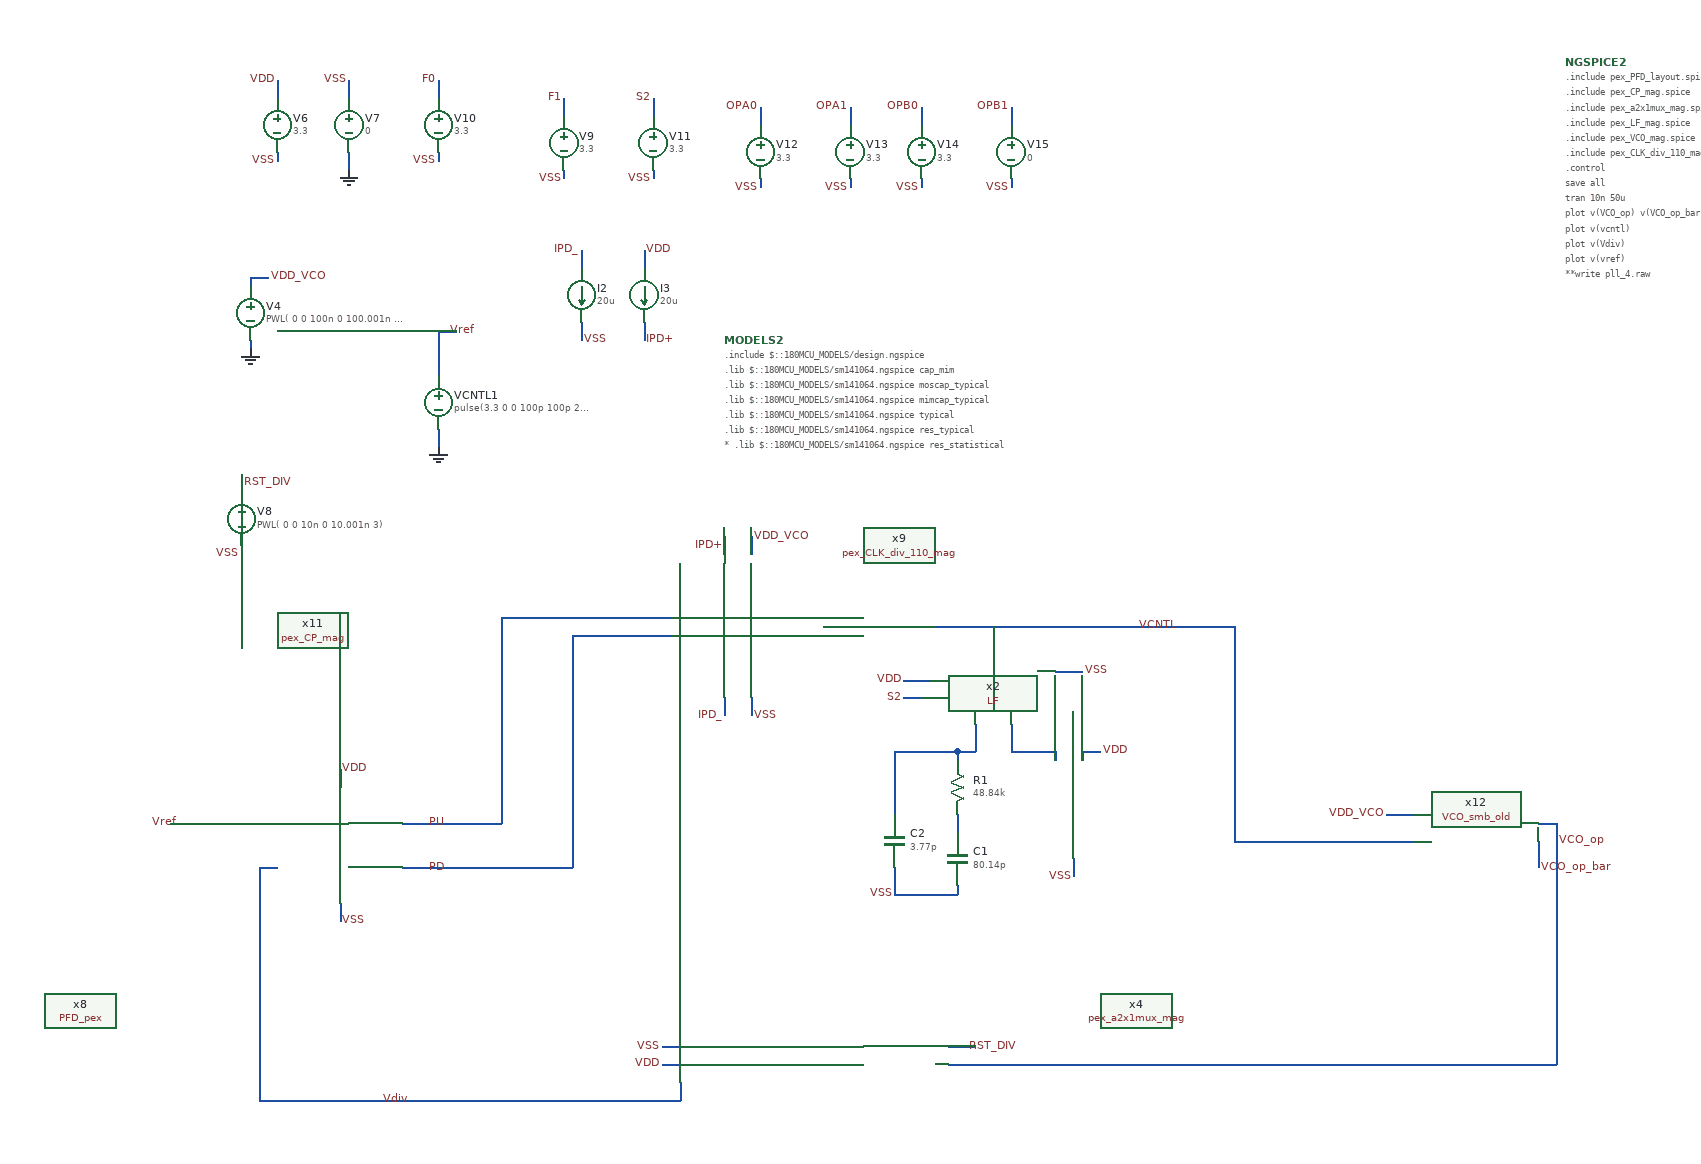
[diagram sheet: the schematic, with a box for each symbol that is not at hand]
v {xschem version=3.1.0 file_version=1.2
}
G {}
K {}
V {}
S {}
E {}
N 2610 -1220 2610 -1200 {
lab=VDD}
N 2610 -1070 2610 -1050 {
lab=VSS}
N 2520 -1160 2540 -1160 {
lab=Vref}
N 2520 -1110 2540 -1110 {
lab=Vdiv}
N 2680 -1110 2700 -1110 {
lab=PD}
N 2440 -1160 2500 -1160 {
lab=Vref}
N 2500 -1160 2520 -1160 {
lab=Vref}
N 2700 -1160 2790 -1160 {
lab=PU}
N 2700 -1110 2790 -1110 {
lab=PD}
N 2520 -1110 2520 -980 {
lab=Vdiv}
N 2520 -880 2520 -850 {
lab=Vdiv}
N 2530 -850 2820 -850 {
lab=Vdiv}
N 2520 -980 2520 -880 {
lab=Vdiv}
N 2520 -850 2530 -850 {
lab=Vdiv}
N 2680 -1160 2700 -1160 {
lab=PU}
N 2720 -1600 2720 -1580 {
lab=GND}
N 2510 -1700 2510 -1690 {
lab=GND}
N 2720 -1710 2740 -1710 {
lab=Vref}
N 2540 -1910 2540 -1900 {
lab=VSS}
N 2540 -1990 2540 -1970 {
lab=VDD}
N 2620 -1990 2620 -1970 {
lab=VSS}
N 2620 -1910 2620 -1890 {
lab=GND}
N 2820 -850 2990 -850 {
lab=Vdiv}
N 3320 -890 3970 -890 {
lab=VCO_op}
N 2500 -1470 2500 -1460 {
lab=VSS}
N 2500 -1550 2500 -1530 {
lab=RST_DIV}
N 3970 -1140 3970 -1120 {
lab=VCO_op}
N 2720 -1710 2720 -1660 {
lab=Vref}
N 3290 -890 3310 -890 {
lab=VCO_op}
N 3310 -890 3320 -890 {
lab=VCO_op}
N 3970 -1120 3970 -890 {
lab=VCO_op}
N 2510 -1770 2510 -1760 {
lab=VDD_VCO}
N 2510 -1770 2530 -1770 {
lab=VDD_VCO}
N 2860 -1890 2860 -1880 {
lab=VSS}
N 2860 -1970 2860 -1950 {
lab=F1}
N 2720 -1910 2720 -1900 {
lab=VSS}
N 2720 -1990 2720 -1970 {
lab=F0}
N 2960 -1890 2960 -1880 {
lab=VSS}
N 2960 -1970 2960 -1950 {
lab=S2}
N 3080 -1880 3080 -1870 {
lab=VSS}
N 3080 -1960 3080 -1940 {
lab=OPA0}
N 3180 -1880 3180 -1870 {
lab=VSS}
N 3180 -1960 3180 -1940 {
lab=OPA1}
N 3260 -1880 3260 -1870 {
lab=VSS}
N 3260 -1960 3260 -1940 {
lab=OPB0}
N 3360 -1880 3360 -1870 {
lab=VSS}
N 3360 -1960 3360 -1940 {
lab=OPB1}
N 3070 -1480 3070 -1460 {
lab=VDD_VCO}
N 3070 -1300 3070 -1280 {
lab=VSS}
N 2960 -1390 2980 -1390 {
lab=PU}
N 2960 -1370 2980 -1370 {
lab=PD}
N 3040 -1480 3040 -1460 {
lab=IPD+}
N 3040 -1300 3040 -1280 {
lab=IPD_}
N 2880 -1720 2880 -1700 {
lab=VSS}
N 2950 -1720 2950 -1700 {
lab=IPD+}
N 2880 -1800 2880 -1780 {
lab=IPD_}
N 2950 -1800 2950 -1780 {
lab=VDD}
N 2420 -1160 2450 -1160 {
lab=Vref}
N 3610 -1140 3650 -1140 {
lab=VCNTL}
N 3970 -1160 3970 -1140 {
lab=VCO_op}
N 3950 -1160 3970 -1160 {
lab=VCO_op}
N 3950 -1140 3950 -1110 {
lab=VCO_op_bar}
N 2990 -870 2990 -850 {
lab=Vdiv}
N 2980 -890 2990 -890 {
lab=VDD}
N 2970 -890 2980 -890 {
lab=VDD}
N 2970 -910 2990 -910 {
lab=VSS}
N 3290 -910 3320 -910 {
lab=RST_DIV}
N 3780 -1170 3810 -1170 {
lab=VDD_VCO}
N 3650 -1140 3810 -1140 {
lab=VCNTL}
N 3430 -1120 3430 -1100 {
lab=VSS}
N 3440 -1240 3440 -1230 {
lab=VDD}
N 3440 -1240 3460 -1240 {
lab=VDD}
N 3240 -1300 3260 -1300 {
lab=S2}
N 3240 -1320 3260 -1320 {
lab=VDD}
N 3410 -1330 3440 -1330 {
lab=VSS}
N 3230 -1110 3230 -1080 {
lab=VSS}
N 3230 -1080 3300 -1080 {
lab=VSS}
N 3230 -1240 3230 -1170 {
lab=#net1}
N 3230 -1240 3300 -1240 {
lab=#net1}
N 3300 -1240 3300 -1230 {
lab=#net1}
N 3260 -1320 3270 -1320 {
lab=VDD}
N 3220 -1380 3400 -1380 {
lab=VCNTL}
N 3300 -1170 3300 -1150 {
lab=#net2}
N 3300 -1090 3300 -1080 {
lab=VSS}
N 3300 -1240 3320 -1240 {
lab=#net1}
N 3320 -1270 3320 -1240 {
lab=#net1}
N 3410 -1240 3410 -1230 {
lab=#net3}
N 3360 -1240 3410 -1240 {
lab=#net3}
N 3360 -1270 3360 -1240 {
lab=#net3}
N 3340 -1380 3340 -1370 {
lab=VCNTL}
N 3610 -1370 3610 -1140 {
lab=VCNTL}
N 3610 -1380 3610 -1370 {
lab=VCNTL}
N 3400 -1380 3610 -1380 {
lab=VCNTL}
N 3150 -1380 3220 -1380 {
lab=VCNTL}
N 2790 -1390 2960 -1390 {
lab=PU}
N 2790 -1390 2790 -1160 {
lab=PU}
N 2790 -1110 2870 -1110 {
lab=PD}
N 2870 -1370 2870 -1110 {
lab=PD}
N 2870 -1370 2960 -1370 {
lab=PD}
C {devices/lab_pin.sym} 2610 -1220 2 0 {name=p22 sig_type=std_logic lab=VDD}
C {devices/lab_wire.sym} 2610 -1050 2 0 {name=p23 sig_type=std_logic lab=VSS}
C {devices/lab_pin.sym} 2690 -850 3 0 {name=p25 sig_type=std_logic lab=Vdiv
}
C {devices/lab_pin.sym} 3970 -1140 2 0 {name=p26 sig_type=std_logic lab=VCO_op
}
C {devices/vsource.sym} 2720 -1630 0 0 {name=VCNTL1 value="pulse(3.3 0 0 100p 100p 250n 500n)"}
C {devices/gnd.sym} 2720 -1580 0 0 {name=l4 lab=GND}
C {devices/gnd.sym} 2510 -1690 0 0 {name=l5 lab=GND}
C {devices/vsource.sym} 2510 -1730 0 0 {name=V4 value=" PWL( 0 0 100n 0 100.001n 3.3)"}
C {devices/code_shown.sym} 3980 -2010 0 1 {name=NGSPICE2 only_toplevel=true
value="
.include "pex_PFD_layout.spice"
.include "pex_CP_mag.spice"
.include "pex_a2x1mux_mag.spice"
.include "pex_LF_mag.spice"
.include "pex_VCO_mag.spice"
.include "pex_CLK_div_110_mag.spice"
.control
save all
tran 10n 50u 
plot v(VCO_op) v(VCO_op_bar)+4
plot v(vcntl)
plot v(Vdiv)
plot v(vref)
**write pll_4.raw
.endc
"}
C {devices/vsource.sym} 2540 -1940 0 0 {name=V6 value=3.3}
C {devices/vsource.sym} 2620 -1940 0 0 {name=V7 value=0}
C {devices/lab_wire.sym} 2620 -1990 0 0 {name=p27 sig_type=std_logic lab=VSS}
C {devices/lab_wire.sym} 2540 -1900 0 0 {name=p29 sig_type=std_logic lab=VSS
}
C {devices/lab_wire.sym} 2540 -1990 0 0 {name=p30 sig_type=std_logic lab=VDD}
C {devices/gnd.sym} 2620 -1890 0 0 {name=l6 lab=GND}
C {devices/lab_pin.sym} 3950 -1110 2 0 {name=p31 sig_type=std_logic lab=VCO_op_bar
}
C {devices/lab_pin.sym} 2530 -1770 2 0 {name=p32 sig_type=std_logic lab=VDD_VCO}
C {devices/lab_pin.sym} 2730 -1710 2 0 {name=p33 sig_type=std_logic lab=Vref
}
C {devices/lab_wire.sym} 2500 -1460 0 0 {name=p34 sig_type=std_logic lab=VSS
}
C {devices/vsource.sym} 2500 -1500 0 0 {name=V8 value=" PWL( 0 0 10n 0 10.001n 3)"}
C {devices/lab_pin.sym} 2730 -1160 1 0 {name=p37 sig_type=std_logic lab=PU}
C {devices/lab_pin.sym} 2730 -1110 1 0 {name=p40 sig_type=std_logic lab=PD}
C {devices/vsource.sym} 2860 -1920 0 0 {name=V9 value=3.3}
C {devices/lab_wire.sym} 2860 -1880 0 0 {name=p41 sig_type=std_logic lab=VSS
}
C {devices/lab_wire.sym} 2860 -1970 0 0 {name=p42 sig_type=std_logic lab=F1}
C {devices/vsource.sym} 2720 -1940 0 0 {name=V10 value=3.3}
C {devices/lab_wire.sym} 2720 -1900 0 0 {name=p43 sig_type=std_logic lab=VSS
}
C {devices/lab_wire.sym} 2720 -1990 0 0 {name=p44 sig_type=std_logic lab=F0}
C {devices/vsource.sym} 2960 -1920 0 0 {name=V11 value=3.3}
C {devices/lab_wire.sym} 2960 -1880 0 0 {name=p45 sig_type=std_logic lab=VSS
}
C {devices/lab_wire.sym} 2960 -1970 0 0 {name=p46 sig_type=std_logic lab=S2}
C {devices/vsource.sym} 3080 -1910 0 0 {name=V12 value=3.3}
C {devices/lab_wire.sym} 3080 -1870 0 0 {name=p59 sig_type=std_logic lab=VSS
}
C {devices/lab_wire.sym} 3080 -1960 0 0 {name=p60 sig_type=std_logic lab=OPA0}
C {devices/vsource.sym} 3180 -1910 0 0 {name=V13 value=3.3}
C {devices/lab_wire.sym} 3180 -1870 0 0 {name=p61 sig_type=std_logic lab=VSS
}
C {devices/lab_wire.sym} 3180 -1960 0 0 {name=p62 sig_type=std_logic lab=OPA1}
C {devices/vsource.sym} 3260 -1910 0 0 {name=V14 value=3.3}
C {devices/lab_wire.sym} 3260 -1870 0 0 {name=p63 sig_type=std_logic lab=VSS
}
C {devices/lab_wire.sym} 3260 -1960 0 0 {name=p64 sig_type=std_logic lab=OPB0
}
C {devices/vsource.sym} 3360 -1910 0 0 {name=V15 value=0}
C {devices/lab_wire.sym} 3360 -1870 0 0 {name=p65 sig_type=std_logic lab=VSS
}
C {devices/lab_wire.sym} 3360 -1960 0 0 {name=p66 sig_type=std_logic lab=OPB1}
C {devices/lab_pin.sym} 2500 -1540 2 0 {name=p67 sig_type=std_logic lab=RST_DIV}
C {devices/lab_wire.sym} 3070 -1280 2 0 {name=p68 sig_type=std_logic lab=VSS}
C {devices/lab_wire.sym} 3040 -1470 0 0 {name=p70 sig_type=std_logic lab=IPD+}
C {devices/lab_wire.sym} 3040 -1280 0 0 {name=p71 sig_type=std_logic lab=IPD_}
C {devices/isource.sym} 2880 -1750 0 0 {name=I2 value=20u}
C {devices/isource.sym} 2950 -1750 0 0 {name=I3 value=20u}
C {devices/lab_wire.sym} 2880 -1800 0 0 {name=p72 sig_type=std_logic lab=IPD_}
C {devices/lab_wire.sym} 2950 -1700 2 0 {name=p73 sig_type=std_logic lab=IPD+}
C {devices/lab_wire.sym} 2880 -1700 2 0 {name=p74 sig_type=std_logic lab=VSS}
C {devices/lab_wire.sym} 2950 -1800 2 0 {name=p75 sig_type=std_logic lab=VDD}
C {devices/lab_pin.sym} 2430 -1160 0 0 {name=p76 sig_type=std_logic lab=Vref
}
C {devices/code_shown.sym} 3040 -1700 0 0 {name=MODELS2 only_toplevel=true
format="tcleval( @value )"
value="
.include $::180MCU_MODELS/design.ngspice
.lib $::180MCU_MODELS/sm141064.ngspice cap_mim
.lib $::180MCU_MODELS/sm141064.ngspice moscap_typical
.lib $::180MCU_MODELS/sm141064.ngspice mimcap_typical
.lib $::180MCU_MODELS/sm141064.ngspice typical
.lib $::180MCU_MODELS/sm141064.ngspice res_typical
* .lib $::180MCU_MODELS/sm141064.ngspice res_statistical
"}
C {PFD_pex.sym} 2320 -950 0 0 {name=x8}
C {devices/lab_wire.sym} 2970 -910 0 0 {name=p78 sig_type=std_logic lab=VSS}
C {devices/lab_pin.sym} 2970 -890 0 0 {name=p79 sig_type=std_logic lab=VDD}
C {devices/lab_pin.sym} 3310 -910 2 0 {name=p80 sig_type=std_logic lab=RST_DIV}
C {pex_CLK_div_110_mag.sym} 3140 -890 0 1 {name=x9}
C {pex_CP_mag.sym} 2490 -1180 0 0 {name=x11}
C {devices/lab_pin.sym} 3070 -1480 2 0 {name=p81 sig_type=std_logic lab=VDD_VCO}
C {VCO_smb_old.sym} 3960 -1150 0 0 {name=x12}
C {devices/lab_pin.sym} 3780 -1170 0 0 {name=p89 sig_type=std_logic lab=VDD_VCO}
C {devices/lab_wire.sym} 3430 -1100 2 1 {name=p5 sig_type=std_logic lab=VSS}
C {devices/lab_wire.sym} 3500 -1380 2 0 {name=p20 sig_type=std_logic lab=VCNTL}
C {devices/lab_wire.sym} 3460 -1240 0 1 {name=p21 sig_type=std_logic lab=VDD}
C {LF.sym} 3570 -1070 0 1 {name=x2}
C {devices/lab_wire.sym} 3440 -1330 2 0 {name=p6 sig_type=std_logic lab=VSS}
C {devices/lab_wire.sym} 3240 -1320 2 1 {name=p1 sig_type=std_logic lab=VDD}
C {devices/lab_wire.sym} 3240 -1300 1 1 {name=p2 sig_type=std_logic lab=S2}
C {devices/capa.sym} 3300 -1120 0 0 {name=C1
m=1
value=80.14p
footprint=1206
device="ceramic capacitor"}
C {devices/capa.sym} 3230 -1140 0 0 {name=C2
m=1
value=3.77p
footprint=1206
device="ceramic capacitor"}
C {devices/res.sym} 3300 -1200 0 0 {name=R1
value=48.84k
footprint=1206
device=resistor
m=1}
C {devices/lab_wire.sym} 3230 -1080 2 1 {name=p3 sig_type=std_logic lab=VSS}
C {pex_a2x1mux_mag.sym} 3500 -950 3 0 {name=x4}
